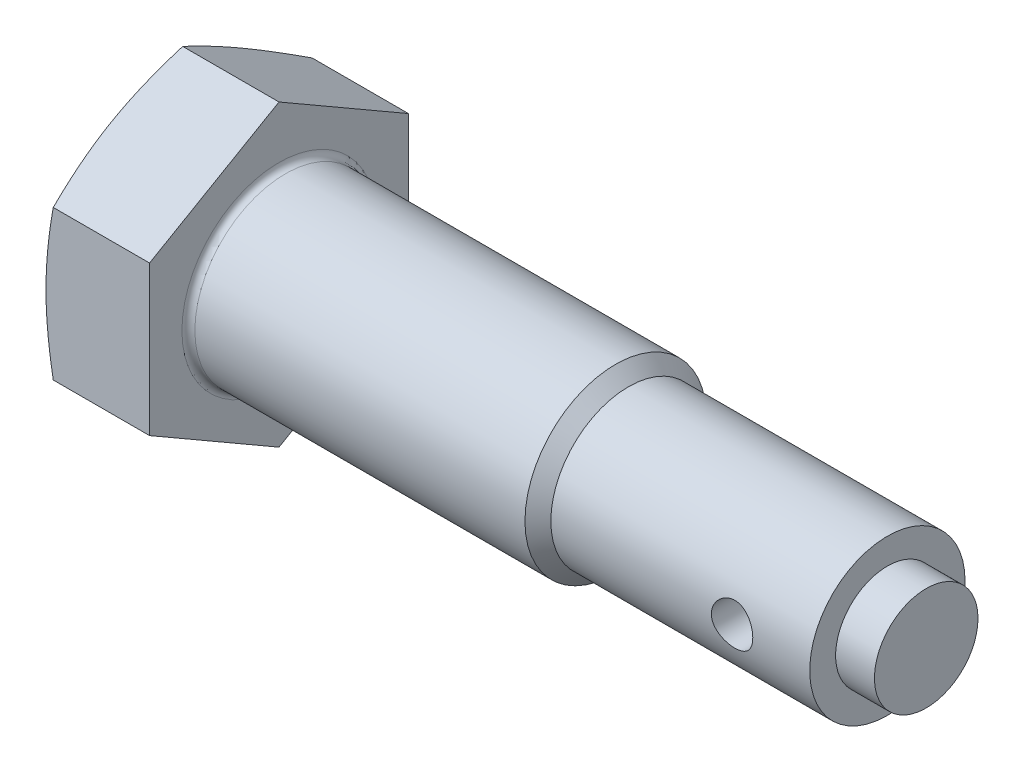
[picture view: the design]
ISO-10303-21;
HEADER;
FILE_DESCRIPTION(('STEP AP214'),'2;1');
FILE_NAME('part.step','',(''),(''),'','','');
FILE_SCHEMA(('AUTOMOTIVE_DESIGN { 1 0 10303 214 1 1 1 1 }'));
ENDSEC;
DATA;
#1=APPLICATION_CONTEXT('core data for automotive mechanical design processes');
#2=APPLICATION_PROTOCOL_DEFINITION('international standard','automotive_design',2000,#1);
#3=PRODUCT_CONTEXT('',#1,'mechanical');
#4=PRODUCT('Part','Part','',(#3));
#5=PRODUCT_RELATED_PRODUCT_CATEGORY('part','',(#4));
#6=PRODUCT_DEFINITION_FORMATION('','',#4);
#7=PRODUCT_DEFINITION_CONTEXT('part definition',#1,'design');
#8=PRODUCT_DEFINITION('design','',#6,#7);
#9=PRODUCT_DEFINITION_SHAPE('','',#8);
#10=(LENGTH_UNIT() NAMED_UNIT(*) SI_UNIT(.MILLI.,.METRE.));
#11=(NAMED_UNIT(*) PLANE_ANGLE_UNIT() SI_UNIT($,.RADIAN.));
#12=(NAMED_UNIT(*) SI_UNIT($,.STERADIAN.) SOLID_ANGLE_UNIT());
#13=UNCERTAINTY_MEASURE_WITH_UNIT(LENGTH_MEASURE(1.E-05),#10,'distance_accuracy_value','');
#14=(GEOMETRIC_REPRESENTATION_CONTEXT(3) GLOBAL_UNCERTAINTY_ASSIGNED_CONTEXT((#13)) GLOBAL_UNIT_ASSIGNED_CONTEXT((#10,
#11,#12)) REPRESENTATION_CONTEXT('',''));
#15=CARTESIAN_POINT('',(0.,0.,0.));
#16=DIRECTION('',(0.,0.,1.));
#17=DIRECTION('',(1.,0.,0.));
#18=AXIS2_PLACEMENT_3D('',#15,#16,#17);
#19=CARTESIAN_POINT('',(4.,-2.88675134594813,4.99999999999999));
#20=DIRECTION('',(0.,0.866025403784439,-0.5));
#21=DIRECTION('',(0.,0.5,0.866025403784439));
#22=AXIS2_PLACEMENT_3D('',#19,#20,#21);
#23=PLANE('',#22);
#24=CARTESIAN_POINT('',(0.281573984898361,-5.77361816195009,-0.000199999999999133));
#25=CARTESIAN_POINT('',(0.238042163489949,-5.65406193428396,0.206877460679));
#26=CARTESIAN_POINT('',(0.198442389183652,-5.53411145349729,0.414637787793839));
#27=CARTESIAN_POINT('',(0.128772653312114,-5.29343053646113,0.831509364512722));
#28=CARTESIAN_POINT('',(0.0987101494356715,-5.17269956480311,1.04062154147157));
#29=CARTESIAN_POINT('',(0.0500848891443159,-4.9317975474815,1.45787607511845));
#30=CARTESIAN_POINT('',(0.0314160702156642,-4.81163200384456,1.66600890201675));
#31=CARTESIAN_POINT('',(0.00637593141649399,-4.57101989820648,2.08276129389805));
#32=CARTESIAN_POINT('',(0.,-4.45057345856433,2.29138064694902));
#33=CARTESIAN_POINT('',(0.,-4.20968057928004,2.70861935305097));
#34=CARTESIAN_POINT('',(0.00637593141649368,-4.0892341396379,2.91723870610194));
#35=CARTESIAN_POINT('',(0.0314160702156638,-3.84862203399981,3.33399109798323));
#36=CARTESIAN_POINT('',(0.0500848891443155,-3.72845649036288,3.54212392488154));
#37=CARTESIAN_POINT('',(0.0987101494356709,-3.48755447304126,3.95937845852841));
#38=CARTESIAN_POINT('',(0.128772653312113,-3.36682350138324,4.16849063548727));
#39=CARTESIAN_POINT('',(0.198442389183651,-3.12614258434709,4.58536221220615));
#40=CARTESIAN_POINT('',(0.238042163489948,-3.00619210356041,4.79312253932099));
#41=CARTESIAN_POINT('',(0.28157398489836,-2.88663587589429,5.00019999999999));
#42=B_SPLINE_CURVE_WITH_KNOTS('',3,(#24,#25,#26,#27,#28,#29,#30,#31,#32,#33,#34,#35,#36,#37,#38,
#39,#40,#41),.UNSPECIFIED.,.F.,.F.,(4,2,2,2,2,2,2,2,4),(0.,0.729203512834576,1.45897583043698,
2.18184682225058,2.90444658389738,3.62704634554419,4.34991733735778,5.07968965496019,
5.80889316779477),.UNSPECIFIED.);
#43=CARTESIAN_POINT('',(0.28153195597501,-5.77350269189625,0.));
#44=VERTEX_POINT('',#43);
#45=CARTESIAN_POINT('',(0.,-4.33012701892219,2.5));
#46=VERTEX_POINT('',#45);
#47=EDGE_CURVE('E302',#44,#46,#42,.T.);
#48=ORIENTED_EDGE('',*,*,#47,.F.);
#49=DIRECTION('',(-1.,0.,0.));
#50=VECTOR('',#49,1.);
#51=CARTESIAN_POINT('',(4.,-5.77350269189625,0.));
#52=LINE('',#51,#50);
#53=CARTESIAN_POINT('',(4.,-5.77350269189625,0.));
#54=VERTEX_POINT('',#53);
#55=EDGE_CURVE('E166',#54,#44,#52,.T.);
#56=ORIENTED_EDGE('',*,*,#55,.F.);
#57=DIRECTION('',(0.,-0.5,-0.866025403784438));
#58=VECTOR('',#57,1.);
#59=CARTESIAN_POINT('',(4.,-2.88675134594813,4.99999999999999));
#60=LINE('',#59,#58);
#61=CARTESIAN_POINT('',(4.,-2.88675134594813,4.99999999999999));
#62=VERTEX_POINT('',#61);
#63=EDGE_CURVE('E285',#62,#54,#60,.T.);
#64=ORIENTED_EDGE('',*,*,#63,.F.);
#65=DIRECTION('',(-1.,0.,0.));
#66=VECTOR('',#65,1.);
#67=CARTESIAN_POINT('',(4.,-2.88675134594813,4.99999999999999));
#68=LINE('',#67,#66);
#69=CARTESIAN_POINT('',(0.28153195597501,-2.88675134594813,4.99999999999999));
#70=VERTEX_POINT('',#69);
#71=EDGE_CURVE('E152',#62,#70,#68,.T.);
#72=ORIENTED_EDGE('',*,*,#71,.T.);
#73=EDGE_CURVE('E150',#46,#70,#42,.T.);
#74=ORIENTED_EDGE('',*,*,#73,.F.);
#75=EDGE_LOOP('',(#48,#56,#64,#72,#74));
#76=FACE_BOUND('',#75,.T.);
#77=ADVANCED_FACE('F49',(#76),#23,.F.);
#78=CARTESIAN_POINT('',(4.,-5.77350269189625,0.));
#79=DIRECTION('',(0.,0.866025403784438,0.5));
#80=DIRECTION('',(0.,-0.5,0.866025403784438));
#81=AXIS2_PLACEMENT_3D('',#78,#79,#80);
#82=PLANE('',#81);
#83=CARTESIAN_POINT('',(0.281573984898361,-2.88663587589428,-5.00019999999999));
#84=CARTESIAN_POINT('',(0.238042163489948,-3.00619210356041,-4.79312253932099));
#85=CARTESIAN_POINT('',(0.198442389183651,-3.12614258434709,-4.58536221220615));
#86=CARTESIAN_POINT('',(0.128772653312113,-3.36682350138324,-4.16849063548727));
#87=CARTESIAN_POINT('',(0.0987101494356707,-3.48755447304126,-3.95937845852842));
#88=CARTESIAN_POINT('',(0.050084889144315,-3.72845649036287,-3.54212392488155));
#89=CARTESIAN_POINT('',(0.0314160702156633,-3.84862203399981,-3.33399109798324));
#90=CARTESIAN_POINT('',(0.00637593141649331,-4.0892341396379,-2.91723870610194));
#91=CARTESIAN_POINT('',(0.,-4.20968057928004,-2.70861935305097));
#92=CARTESIAN_POINT('',(0.,-4.45057345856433,-2.29138064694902));
#93=CARTESIAN_POINT('',(0.00637593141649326,-4.57101989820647,-2.08276129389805));
#94=CARTESIAN_POINT('',(0.0314160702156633,-4.81163200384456,-1.66600890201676));
#95=CARTESIAN_POINT('',(0.050084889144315,-4.9317975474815,-1.45787607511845));
#96=CARTESIAN_POINT('',(0.0987101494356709,-5.17269956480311,-1.04062154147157));
#97=CARTESIAN_POINT('',(0.128772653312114,-5.29343053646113,-0.831509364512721));
#98=CARTESIAN_POINT('',(0.198442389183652,-5.53411145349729,-0.414637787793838));
#99=CARTESIAN_POINT('',(0.238042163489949,-5.65406193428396,-0.206877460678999));
#100=CARTESIAN_POINT('',(0.281573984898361,-5.77361816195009,0.000199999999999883));
#101=B_SPLINE_CURVE_WITH_KNOTS('',3,(#83,#84,#85,#86,#87,#88,#89,#90,#91,#92,#93,#94,#95,#96,
#97,#98,#99,#100),.UNSPECIFIED.,.F.,.F.,(4,2,2,2,2,2,2,2,4),(0.,0.729203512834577,
1.45897583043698,2.18184682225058,2.90444658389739,3.6270463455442,4.34991733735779,
5.0796896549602,5.80889316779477),.UNSPECIFIED.);
#102=CARTESIAN_POINT('',(0.28153195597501,-2.88675134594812,-4.99999999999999));
#103=VERTEX_POINT('',#102);
#104=CARTESIAN_POINT('',(0.,-4.33012701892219,-2.5));
#105=VERTEX_POINT('',#104);
#106=EDGE_CURVE('E243',#103,#105,#101,.T.);
#107=ORIENTED_EDGE('',*,*,#106,.F.);
#108=DIRECTION('',(-1.,0.,0.));
#109=VECTOR('',#108,1.);
#110=CARTESIAN_POINT('',(4.,-2.88675134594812,-4.99999999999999));
#111=LINE('',#110,#109);
#112=CARTESIAN_POINT('',(4.,-2.88675134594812,-4.99999999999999));
#113=VERTEX_POINT('',#112);
#114=EDGE_CURVE('E161',#113,#103,#111,.T.);
#115=ORIENTED_EDGE('',*,*,#114,.F.);
#116=DIRECTION('',(0.,0.5,-0.866025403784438));
#117=VECTOR('',#116,1.);
#118=CARTESIAN_POINT('',(4.,-5.77350269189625,0.));
#119=LINE('',#118,#117);
#120=EDGE_CURVE('E281',#54,#113,#119,.T.);
#121=ORIENTED_EDGE('',*,*,#120,.F.);
#122=ORIENTED_EDGE('',*,*,#55,.T.);
#123=EDGE_CURVE('E239',#105,#44,#101,.T.);
#124=ORIENTED_EDGE('',*,*,#123,.F.);
#125=EDGE_LOOP('',(#107,#115,#121,#122,#124));
#126=FACE_BOUND('',#125,.T.);
#127=ADVANCED_FACE('F255',(#126),#82,.F.);
#128=CARTESIAN_POINT('',(4.,-2.88675134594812,-4.99999999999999));
#129=DIRECTION('',(0.,0.,1.));
#130=DIRECTION('',(1.,0.,0.));
#131=AXIS2_PLACEMENT_3D('',#128,#129,#130);
#132=PLANE('',#131);
#133=CARTESIAN_POINT('',(1.50439512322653,-7.64310251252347,-4.99999999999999));
#134=CARTESIAN_POINT('',(1.43551180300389,-7.4168844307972,-4.99999999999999));
#135=CARTESIAN_POINT('',(1.36743226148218,-7.19041704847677,-4.99999999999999));
#136=CARTESIAN_POINT('',(1.23332538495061,-6.73685676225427,-4.99999999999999));
#137=CARTESIAN_POINT('',(1.1672982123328,-6.5097638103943,-4.99999999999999));
#138=CARTESIAN_POINT('',(1.03763088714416,-6.05443677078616,-4.99999999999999));
#139=CARTESIAN_POINT('',(0.973995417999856,-5.82620134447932,-4.99999999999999));
#140=CARTESIAN_POINT('',(0.849856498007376,-5.36888148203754,-4.99999999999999));
#141=CARTESIAN_POINT('',(0.7893529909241,-5.1397970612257,-4.99999999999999));
#142=CARTESIAN_POINT('',(0.672973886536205,-4.68345086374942,-4.99999999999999));
#143=CARTESIAN_POINT('',(0.617050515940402,-4.45620133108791,-4.99999999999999));
#144=CARTESIAN_POINT('',(0.50996822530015,-4.00058448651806,-4.99999999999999));
#145=CARTESIAN_POINT('',(0.458809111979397,-3.77221722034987,-4.99999999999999));
#146=CARTESIAN_POINT('',(0.362442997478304,-3.31429429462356,-4.99999999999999));
#147=CARTESIAN_POINT('',(0.317234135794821,-3.08473902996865,-4.99999999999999));
#148=CARTESIAN_POINT('',(0.234146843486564,-2.62429577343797,-4.99999999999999));
#149=CARTESIAN_POINT('',(0.196268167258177,-2.3934078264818,-4.99999999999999));
#150=CARTESIAN_POINT('',(0.133130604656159,-1.95629809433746,-4.99999999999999));
#151=CARTESIAN_POINT('',(0.10693296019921,-1.75021318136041,-4.99999999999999));
#152=CARTESIAN_POINT('',(0.0625865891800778,-1.3371719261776,-4.99999999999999));
#153=CARTESIAN_POINT('',(0.0444376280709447,-1.13021560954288,-4.99999999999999));
#154=CARTESIAN_POINT('',(0.0170626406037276,-0.71585133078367,-4.99999999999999));
#155=CARTESIAN_POINT('',(0.00783030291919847,-0.508443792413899,-4.99999999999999));
#156=CARTESIAN_POINT('',(-0.00124400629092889,-0.0934212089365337,-4.99999999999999));
#157=CARTESIAN_POINT('',(-0.00108604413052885,0.114193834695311,-4.99999999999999));
#158=CARTESIAN_POINT('',(0.00863625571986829,0.530253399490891,-4.99999999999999));
#159=CARTESIAN_POINT('',(0.0182482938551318,0.738696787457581,-4.99999999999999));
#160=CARTESIAN_POINT('',(0.0464363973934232,1.15497131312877,-4.99999999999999));
#161=CARTESIAN_POINT('',(0.0650126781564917,1.36280243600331,-4.99999999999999));
#162=CARTESIAN_POINT('',(0.110260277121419,1.77774980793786,-4.99999999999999));
#163=CARTESIAN_POINT('',(0.136938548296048,1.98486528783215,-4.99999999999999));
#164=CARTESIAN_POINT('',(0.19730798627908,2.3980600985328,-4.99999999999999));
#165=CARTESIAN_POINT('',(0.230999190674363,2.60413942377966,-4.99999999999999));
#166=CARTESIAN_POINT('',(0.306236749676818,3.02610647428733,-4.99999999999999));
#167=CARTESIAN_POINT('',(0.348104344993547,3.24193641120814,-4.99999999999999));
#168=CARTESIAN_POINT('',(0.437228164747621,3.67248794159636,-4.99999999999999));
#169=CARTESIAN_POINT('',(0.484484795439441,3.88720945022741,-4.99999999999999));
#170=CARTESIAN_POINT('',(0.58339431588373,4.3156971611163,-4.99999999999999));
#171=CARTESIAN_POINT('',(0.635048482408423,4.52946306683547,-4.99999999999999));
#172=CARTESIAN_POINT('',(0.741913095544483,4.95609429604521,-4.99999999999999));
#173=CARTESIAN_POINT('',(0.797123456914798,5.16895964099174,-4.99999999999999));
#174=CARTESIAN_POINT('',(0.910507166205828,5.59418863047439,-4.99999999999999));
#175=CARTESIAN_POINT('',(0.96868421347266,5.80655128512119,-4.99999999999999));
#176=CARTESIAN_POINT('',(1.08740866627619,6.23061420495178,-4.99999999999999));
#177=CARTESIAN_POINT('',(1.14795610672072,6.44231446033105,-4.99999999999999));
#178=CARTESIAN_POINT('',(1.33247422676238,7.07649472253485,-4.99999999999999));
#179=CARTESIAN_POINT('',(1.45934162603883,7.49813135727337,-4.99999999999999));
#180=CARTESIAN_POINT('',(1.71694117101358,8.33511686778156,-4.99999999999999));
#181=CARTESIAN_POINT('',(1.84761520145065,8.75048377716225,-4.99999999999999));
#182=CARTESIAN_POINT('',(2.11267795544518,9.5800502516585,-4.99999999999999));
#183=CARTESIAN_POINT('',(2.24706685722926,9.99424975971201,-4.99999999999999));
#184=CARTESIAN_POINT('',(2.51803451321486,10.8201887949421,-4.99999999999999));
#185=CARTESIAN_POINT('',(2.65460302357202,11.2319316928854,-4.99999999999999));
#186=CARTESIAN_POINT('',(2.92978767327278,12.0546955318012,-4.99999999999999));
#187=CARTESIAN_POINT('',(3.06840364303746,12.4657165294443,-4.99999999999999));
#188=CARTESIAN_POINT('',(3.20773627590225,12.8764911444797,-4.99999999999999));
#189=B_SPLINE_CURVE_WITH_KNOTS('',3,(#133,#134,#135,#136,#137,#138,#139,#140,#141,#142,#143,
#144,#145,#146,#147,#148,#149,#150,#151,#152,#153,#154,#155,#156,#157,#158,#159,#160,#161,#162,
#163,#164,#165,#166,#167,#168,#169,#170,#171,#172,#173,#174,#175,#176,#177,#178,#179,#180,#181,
#182,#183,#184,#185,#186,#187,#188),.UNSPECIFIED.,.F.,.F.,(4,2,2,2,2,2,2,2,2,2,2,2,2,2,2,2,2,2,
2,2,2,2,2,2,2,2,2,4),(0.,0.709424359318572,1.41890470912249,2.12970877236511,2.84050006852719,
3.54254782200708,4.24456708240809,4.94636631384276,5.6481420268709,6.27123531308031,
6.89431044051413,7.51694422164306,8.13957360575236,8.76536065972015,9.39116274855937,
10.0175034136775,10.64384743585,11.3033228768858,11.9628480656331,12.6225653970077,
13.2822669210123,13.9428122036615,14.6033672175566,15.9242375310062,17.2305282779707,
18.5368818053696,19.8382785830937,21.139568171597),.UNSPECIFIED.);
#190=CARTESIAN_POINT('',(0.28153195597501,2.88675134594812,-4.99999999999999));
#191=VERTEX_POINT('',#190);
#192=CARTESIAN_POINT('',(0.,0.,-5.));
#193=VERTEX_POINT('',#192);
#194=EDGE_CURVE('E307',#191,#193,#189,.F.);
#195=ORIENTED_EDGE('',*,*,#194,.F.);
#196=DIRECTION('',(-1.,0.,0.));
#197=VECTOR('',#196,1.);
#198=CARTESIAN_POINT('',(4.,2.88675134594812,-4.99999999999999));
#199=LINE('',#198,#197);
#200=CARTESIAN_POINT('',(4.,2.88675134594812,-4.99999999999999));
#201=VERTEX_POINT('',#200);
#202=EDGE_CURVE('E157',#201,#191,#199,.T.);
#203=ORIENTED_EDGE('',*,*,#202,.F.);
#204=DIRECTION('',(0.,1.,0.));
#205=VECTOR('',#204,1.);
#206=CARTESIAN_POINT('',(4.,-2.88675134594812,-4.99999999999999));
#207=LINE('',#206,#205);
#208=EDGE_CURVE('E288',#113,#201,#207,.T.);
#209=ORIENTED_EDGE('',*,*,#208,.F.);
#210=ORIENTED_EDGE('',*,*,#114,.T.);
#211=EDGE_CURVE('E242',#193,#103,#189,.F.);
#212=ORIENTED_EDGE('',*,*,#211,.F.);
#213=EDGE_LOOP('',(#195,#203,#209,#210,#212));
#214=FACE_BOUND('',#213,.T.);
#215=ADVANCED_FACE('F254',(#214),#132,.F.);
#216=CARTESIAN_POINT('',(4.,2.88675134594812,-4.99999999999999));
#217=DIRECTION('',(0.,-0.866025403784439,0.5));
#218=DIRECTION('',(0.,-0.5,-0.866025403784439));
#219=AXIS2_PLACEMENT_3D('',#216,#217,#218);
#220=PLANE('',#219);
#221=CARTESIAN_POINT('',(0.281573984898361,5.77361816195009,0.000199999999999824));
#222=CARTESIAN_POINT('',(0.238042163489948,5.65406193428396,-0.206877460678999));
#223=CARTESIAN_POINT('',(0.198442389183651,5.53411145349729,-0.414637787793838));
#224=CARTESIAN_POINT('',(0.128772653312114,5.29343053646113,-0.831509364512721));
#225=CARTESIAN_POINT('',(0.0987101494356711,5.17269956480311,-1.04062154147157));
#226=CARTESIAN_POINT('',(0.0500848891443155,4.9317975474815,-1.45787607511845));
#227=CARTESIAN_POINT('',(0.0314160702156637,4.81163200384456,-1.66600890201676));
#228=CARTESIAN_POINT('',(0.00637593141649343,4.57101989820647,-2.08276129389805));
#229=CARTESIAN_POINT('',(0.,4.45057345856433,-2.29138064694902));
#230=CARTESIAN_POINT('',(0.,4.20968057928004,-2.70861935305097));
#231=CARTESIAN_POINT('',(0.00637593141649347,4.0892341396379,-2.91723870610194));
#232=CARTESIAN_POINT('',(0.0314160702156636,3.84862203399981,-3.33399109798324));
#233=CARTESIAN_POINT('',(0.0500848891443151,3.72845649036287,-3.54212392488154));
#234=CARTESIAN_POINT('',(0.0987101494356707,3.48755447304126,-3.95937845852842));
#235=CARTESIAN_POINT('',(0.128772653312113,3.36682350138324,-4.16849063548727));
#236=CARTESIAN_POINT('',(0.198442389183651,3.12614258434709,-4.58536221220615));
#237=CARTESIAN_POINT('',(0.238042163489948,3.00619210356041,-4.79312253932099));
#238=CARTESIAN_POINT('',(0.28157398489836,2.88663587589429,-5.00019999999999));
#239=B_SPLINE_CURVE_WITH_KNOTS('',3,(#221,#222,#223,#224,#225,#226,#227,#228,#229,#230,#231,
#232,#233,#234,#235,#236,#237,#238),.UNSPECIFIED.,.F.,.F.,(4,2,2,2,2,2,2,2,4),(0.,
0.729203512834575,1.45897583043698,2.18184682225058,2.90444658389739,3.62704634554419,
4.34991733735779,5.07968965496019,5.80889316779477),.UNSPECIFIED.);
#240=CARTESIAN_POINT('',(0.28153195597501,5.77350269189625,0.));
#241=VERTEX_POINT('',#240);
#242=CARTESIAN_POINT('',(0.,4.33012701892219,-2.5));
#243=VERTEX_POINT('',#242);
#244=EDGE_CURVE('E232',#241,#243,#239,.T.);
#245=ORIENTED_EDGE('',*,*,#244,.F.);
#246=DIRECTION('',(-1.,0.,0.));
#247=VECTOR('',#246,1.);
#248=CARTESIAN_POINT('',(4.,5.77350269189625,0.));
#249=LINE('',#248,#247);
#250=CARTESIAN_POINT('',(4.,5.77350269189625,0.));
#251=VERTEX_POINT('',#250);
#252=EDGE_CURVE('E153',#251,#241,#249,.T.);
#253=ORIENTED_EDGE('',*,*,#252,.F.);
#254=DIRECTION('',(0.,0.5,0.866025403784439));
#255=VECTOR('',#254,1.);
#256=CARTESIAN_POINT('',(4.,2.88675134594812,-4.99999999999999));
#257=LINE('',#256,#255);
#258=EDGE_CURVE('E291',#201,#251,#257,.T.);
#259=ORIENTED_EDGE('',*,*,#258,.F.);
#260=ORIENTED_EDGE('',*,*,#202,.T.);
#261=EDGE_CURVE('E301',#243,#191,#239,.T.);
#262=ORIENTED_EDGE('',*,*,#261,.F.);
#263=EDGE_LOOP('',(#245,#253,#259,#260,#262));
#264=FACE_BOUND('',#263,.T.);
#265=ADVANCED_FACE('F298',(#264),#220,.F.);
#266=CARTESIAN_POINT('',(4.,5.77350269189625,0.));
#267=DIRECTION('',(0.,-0.866025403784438,-0.5));
#268=DIRECTION('',(0.,0.5,-0.866025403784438));
#269=AXIS2_PLACEMENT_3D('',#266,#267,#268);
#270=PLANE('',#269);
#271=CARTESIAN_POINT('',(0.28157398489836,2.88663587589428,5.00019999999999));
#272=CARTESIAN_POINT('',(0.238042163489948,3.00619210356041,4.79312253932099));
#273=CARTESIAN_POINT('',(0.19844238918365,3.12614258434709,4.58536221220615));
#274=CARTESIAN_POINT('',(0.128772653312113,3.36682350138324,4.16849063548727));
#275=CARTESIAN_POINT('',(0.09871014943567,3.48755447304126,3.95937845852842));
#276=CARTESIAN_POINT('',(0.0500848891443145,3.72845649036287,3.54212392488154));
#277=CARTESIAN_POINT('',(0.031416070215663,3.84862203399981,3.33399109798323));
#278=CARTESIAN_POINT('',(0.00637593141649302,4.0892341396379,2.91723870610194));
#279=CARTESIAN_POINT('',(0.,4.20968057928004,2.70861935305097));
#280=CARTESIAN_POINT('',(0.,4.45057345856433,2.29138064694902));
#281=CARTESIAN_POINT('',(0.00637593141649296,4.57101989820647,2.08276129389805));
#282=CARTESIAN_POINT('',(0.0314160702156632,4.81163200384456,1.66600890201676));
#283=CARTESIAN_POINT('',(0.0500848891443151,4.9317975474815,1.45787607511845));
#284=CARTESIAN_POINT('',(0.0987101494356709,5.17269956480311,1.04062154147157));
#285=CARTESIAN_POINT('',(0.128772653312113,5.29343053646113,0.831509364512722));
#286=CARTESIAN_POINT('',(0.198442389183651,5.53411145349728,0.414637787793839));
#287=CARTESIAN_POINT('',(0.238042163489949,5.65406193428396,0.206877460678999));
#288=CARTESIAN_POINT('',(0.281573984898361,5.77361816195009,-0.000199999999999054));
#289=B_SPLINE_CURVE_WITH_KNOTS('',3,(#271,#272,#273,#274,#275,#276,#277,#278,#279,#280,#281,
#282,#283,#284,#285,#286,#287,#288),.UNSPECIFIED.,.F.,.F.,(4,2,2,2,2,2,2,2,4),(0.,
0.729203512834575,1.45897583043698,2.18184682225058,2.90444658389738,3.62704634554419,
4.34991733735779,5.07968965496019,5.80889316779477),.UNSPECIFIED.);
#290=CARTESIAN_POINT('',(0.28153195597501,2.88675134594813,4.99999999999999));
#291=VERTEX_POINT('',#290);
#292=CARTESIAN_POINT('',(0.,4.33012701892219,2.5));
#293=VERTEX_POINT('',#292);
#294=EDGE_CURVE('E131',#291,#293,#289,.T.);
#295=ORIENTED_EDGE('',*,*,#294,.F.);
#296=DIRECTION('',(-1.,0.,0.));
#297=VECTOR('',#296,1.);
#298=CARTESIAN_POINT('',(4.,2.88675134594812,4.99999999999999));
#299=LINE('',#298,#297);
#300=CARTESIAN_POINT('',(4.,2.88675134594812,4.99999999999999));
#301=VERTEX_POINT('',#300);
#302=EDGE_CURVE('E147',#301,#291,#299,.T.);
#303=ORIENTED_EDGE('',*,*,#302,.F.);
#304=DIRECTION('',(0.,-0.5,0.866025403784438));
#305=VECTOR('',#304,1.);
#306=CARTESIAN_POINT('',(4.,5.77350269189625,0.));
#307=LINE('',#306,#305);
#308=EDGE_CURVE('E293',#251,#301,#307,.T.);
#309=ORIENTED_EDGE('',*,*,#308,.F.);
#310=ORIENTED_EDGE('',*,*,#252,.T.);
#311=EDGE_CURVE('E148',#293,#241,#289,.T.);
#312=ORIENTED_EDGE('',*,*,#311,.F.);
#313=EDGE_LOOP('',(#295,#303,#309,#310,#312));
#314=FACE_BOUND('',#313,.T.);
#315=ADVANCED_FACE('F142',(#314),#270,.F.);
#316=CARTESIAN_POINT('',(4.,2.88675134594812,4.99999999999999));
#317=DIRECTION('',(0.,0.,-1.));
#318=DIRECTION('',(-1.,0.,0.));
#319=AXIS2_PLACEMENT_3D('',#316,#317,#318);
#320=PLANE('',#319);
#321=CARTESIAN_POINT('',(1.50439512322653,-7.64310251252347,4.99999999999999));
#322=CARTESIAN_POINT('',(1.43551180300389,-7.4168844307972,4.99999999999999));
#323=CARTESIAN_POINT('',(1.36743226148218,-7.19041704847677,4.99999999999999));
#324=CARTESIAN_POINT('',(1.23332538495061,-6.73685676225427,4.99999999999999));
#325=CARTESIAN_POINT('',(1.1672982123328,-6.5097638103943,4.99999999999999));
#326=CARTESIAN_POINT('',(1.03763088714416,-6.05443677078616,4.99999999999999));
#327=CARTESIAN_POINT('',(0.973995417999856,-5.82620134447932,4.99999999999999));
#328=CARTESIAN_POINT('',(0.849856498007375,-5.36888148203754,4.99999999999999));
#329=CARTESIAN_POINT('',(0.789352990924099,-5.1397970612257,4.99999999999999));
#330=CARTESIAN_POINT('',(0.672973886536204,-4.68345086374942,4.99999999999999));
#331=CARTESIAN_POINT('',(0.617050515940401,-4.45620133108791,4.99999999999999));
#332=CARTESIAN_POINT('',(0.509968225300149,-4.00058448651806,4.99999999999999));
#333=CARTESIAN_POINT('',(0.458809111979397,-3.77221722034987,4.99999999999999));
#334=CARTESIAN_POINT('',(0.362442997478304,-3.31429429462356,4.99999999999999));
#335=CARTESIAN_POINT('',(0.317234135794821,-3.08473902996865,4.99999999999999));
#336=CARTESIAN_POINT('',(0.234146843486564,-2.62429577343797,4.99999999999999));
#337=CARTESIAN_POINT('',(0.196268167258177,-2.3934078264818,4.99999999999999));
#338=CARTESIAN_POINT('',(0.133130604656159,-1.95629809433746,4.99999999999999));
#339=CARTESIAN_POINT('',(0.106932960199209,-1.75021318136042,4.99999999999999));
#340=CARTESIAN_POINT('',(0.0625865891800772,-1.3371719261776,4.99999999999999));
#341=CARTESIAN_POINT('',(0.0444376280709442,-1.13021560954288,4.99999999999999));
#342=CARTESIAN_POINT('',(0.0170626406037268,-0.715851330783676,4.99999999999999));
#343=CARTESIAN_POINT('',(0.00783030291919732,-0.508443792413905,4.99999999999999));
#344=CARTESIAN_POINT('',(-0.00124400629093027,-0.0934212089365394,4.99999999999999));
#345=CARTESIAN_POINT('',(-0.00108604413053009,0.114193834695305,4.99999999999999));
#346=CARTESIAN_POINT('',(0.008636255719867,0.530253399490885,4.99999999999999));
#347=CARTESIAN_POINT('',(0.0182482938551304,0.738696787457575,4.99999999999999));
#348=CARTESIAN_POINT('',(0.0464363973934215,1.15497131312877,4.99999999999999));
#349=CARTESIAN_POINT('',(0.0650126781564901,1.36280243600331,4.99999999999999));
#350=CARTESIAN_POINT('',(0.110260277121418,1.77774980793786,4.99999999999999));
#351=CARTESIAN_POINT('',(0.136938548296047,1.98486528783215,4.99999999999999));
#352=CARTESIAN_POINT('',(0.197307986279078,2.3980600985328,4.99999999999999));
#353=CARTESIAN_POINT('',(0.230999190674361,2.60413942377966,4.99999999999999));
#354=CARTESIAN_POINT('',(0.306236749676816,3.02610647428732,4.99999999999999));
#355=CARTESIAN_POINT('',(0.348104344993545,3.24193641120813,4.99999999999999));
#356=CARTESIAN_POINT('',(0.437228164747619,3.67248794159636,4.99999999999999));
#357=CARTESIAN_POINT('',(0.48448479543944,3.88720945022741,4.99999999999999));
#358=CARTESIAN_POINT('',(0.583394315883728,4.31569716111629,4.99999999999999));
#359=CARTESIAN_POINT('',(0.635048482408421,4.52946306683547,4.99999999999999));
#360=CARTESIAN_POINT('',(0.741913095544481,4.95609429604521,4.99999999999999));
#361=CARTESIAN_POINT('',(0.797123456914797,5.16895964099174,4.99999999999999));
#362=CARTESIAN_POINT('',(0.910507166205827,5.59418863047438,4.99999999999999));
#363=CARTESIAN_POINT('',(0.968684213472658,5.80655128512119,4.99999999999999));
#364=CARTESIAN_POINT('',(1.08740866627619,6.23061420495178,4.99999999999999));
#365=CARTESIAN_POINT('',(1.14795610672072,6.44231446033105,4.99999999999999));
#366=CARTESIAN_POINT('',(1.33247422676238,7.07649472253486,4.99999999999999));
#367=CARTESIAN_POINT('',(1.45934162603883,7.49813135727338,4.99999999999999));
#368=CARTESIAN_POINT('',(1.71694117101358,8.33511686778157,4.99999999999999));
#369=CARTESIAN_POINT('',(1.84761520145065,8.75048377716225,4.99999999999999));
#370=CARTESIAN_POINT('',(2.11267795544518,9.5800502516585,4.99999999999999));
#371=CARTESIAN_POINT('',(2.24706685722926,9.99424975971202,4.99999999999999));
#372=CARTESIAN_POINT('',(2.51803451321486,10.8201887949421,4.99999999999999));
#373=CARTESIAN_POINT('',(2.65460302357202,11.2319316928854,4.99999999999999));
#374=CARTESIAN_POINT('',(2.92978767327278,12.0546955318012,4.99999999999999));
#375=CARTESIAN_POINT('',(3.06840364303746,12.4657165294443,4.99999999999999));
#376=CARTESIAN_POINT('',(3.20773627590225,12.8764911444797,4.99999999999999));
#377=B_SPLINE_CURVE_WITH_KNOTS('',3,(#321,#322,#323,#324,#325,#326,#327,#328,#329,#330,#331,
#332,#333,#334,#335,#336,#337,#338,#339,#340,#341,#342,#343,#344,#345,#346,#347,#348,#349,#350,
#351,#352,#353,#354,#355,#356,#357,#358,#359,#360,#361,#362,#363,#364,#365,#366,#367,#368,#369,
#370,#371,#372,#373,#374,#375,#376),.UNSPECIFIED.,.F.,.F.,(4,2,2,2,2,2,2,2,2,2,2,2,2,2,2,2,2,2,
2,2,2,2,2,2,2,2,2,4),(0.,0.709424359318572,1.41890470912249,2.12970877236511,2.84050006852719,
3.54254782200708,4.24456708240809,4.94636631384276,5.6481420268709,6.27123531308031,
6.89431044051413,7.51694422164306,8.13957360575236,8.76536065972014,9.39116274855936,
10.0175034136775,10.64384743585,11.3033228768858,11.9628480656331,12.6225653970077,
13.2822669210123,13.9428122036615,14.6033672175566,15.9242375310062,17.2305282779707,
18.5368818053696,19.8382785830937,21.139568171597),.UNSPECIFIED.);
#378=CARTESIAN_POINT('',(0.,0.,4.99999999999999));
#379=VERTEX_POINT('',#378);
#380=EDGE_CURVE('E138',#70,#379,#377,.T.);
#381=ORIENTED_EDGE('',*,*,#380,.F.);
#382=ORIENTED_EDGE('',*,*,#71,.F.);
#383=DIRECTION('',(0.,-1.,0.));
#384=VECTOR('',#383,1.);
#385=CARTESIAN_POINT('',(4.,2.88675134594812,4.99999999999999));
#386=LINE('',#385,#384);
#387=EDGE_CURVE('E79',#301,#62,#386,.T.);
#388=ORIENTED_EDGE('',*,*,#387,.F.);
#389=ORIENTED_EDGE('',*,*,#302,.T.);
#390=EDGE_CURVE('E132',#379,#291,#377,.T.);
#391=ORIENTED_EDGE('',*,*,#390,.F.);
#392=EDGE_LOOP('',(#381,#382,#388,#389,#391));
#393=FACE_BOUND('',#392,.T.);
#394=ADVANCED_FACE('F155',(#393),#320,.F.);
#395=CARTESIAN_POINT('',(62.4852813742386,0.,0.));
#396=DIRECTION('',(-1.,0.,0.));
#397=DIRECTION('',(0.,0.,1.));
#398=AXIS2_PLACEMENT_3D('',#395,#396,#397);
#399=CYLINDRICAL_SURFACE('',#398,3.);
#400=CARTESIAN_POINT('',(25.3,0.,3.));
#401=CARTESIAN_POINT('',(25.2999989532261,-0.0441018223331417,2.99999933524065));
#402=CARTESIAN_POINT('',(25.2963409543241,-0.0882148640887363,2.99901794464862));
#403=CARTESIAN_POINT('',(25.2818315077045,-0.175170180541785,2.99519829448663));
#404=CARTESIAN_POINT('',(25.2709765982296,-0.218011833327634,2.9923591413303));
#405=CARTESIAN_POINT('',(25.2424513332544,-0.301156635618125,2.98513733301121));
#406=CARTESIAN_POINT('',(25.2247897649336,-0.341462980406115,2.98075666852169));
#407=CARTESIAN_POINT('',(25.1831851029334,-0.418541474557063,2.97091479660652));
#408=CARTESIAN_POINT('',(25.1592415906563,-0.455313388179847,2.96545351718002));
#409=CARTESIAN_POINT('',(25.1051665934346,-0.525131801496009,2.95389845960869));
#410=CARTESIAN_POINT('',(25.0749165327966,-0.558084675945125,2.9477938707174));
#411=CARTESIAN_POINT('',(25.0093406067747,-0.618514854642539,2.93570963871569));
#412=CARTESIAN_POINT('',(24.9740140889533,-0.645991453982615,2.92973001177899));
#413=CARTESIAN_POINT('',(24.8985407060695,-0.695145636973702,2.91846214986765));
#414=CARTESIAN_POINT('',(24.8583214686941,-0.716715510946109,2.91318755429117));
#415=CARTESIAN_POINT('',(24.7746639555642,-0.752750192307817,2.90408590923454));
#416=CARTESIAN_POINT('',(24.7312262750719,-0.76721630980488,2.9002585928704));
#417=CARTESIAN_POINT('',(24.6434017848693,-0.7883076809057,2.89459646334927));
#418=CARTESIAN_POINT('',(24.5990585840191,-0.795102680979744,2.89271859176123));
#419=CARTESIAN_POINT('',(24.5098249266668,-0.801188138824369,2.89103932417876));
#420=CARTESIAN_POINT('',(24.4649345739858,-0.800479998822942,2.89123754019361));
#421=CARTESIAN_POINT('',(24.3772058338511,-0.791714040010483,2.89364951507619));
#422=CARTESIAN_POINT('',(24.3343451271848,-0.783861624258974,2.89580694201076));
#423=CARTESIAN_POINT('',(24.2505726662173,-0.761358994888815,2.90180405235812));
#424=CARTESIAN_POINT('',(24.2096610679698,-0.746708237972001,2.90564387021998));
#425=CARTESIAN_POINT('',(24.1304127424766,-0.710857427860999,2.91462264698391));
#426=CARTESIAN_POINT('',(24.0921102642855,-0.68958536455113,2.91977577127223));
#427=CARTESIAN_POINT('',(24.0195463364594,-0.641146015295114,2.93079291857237));
#428=CARTESIAN_POINT('',(23.9852856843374,-0.613977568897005,2.93665708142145));
#429=CARTESIAN_POINT('',(23.9206044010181,-0.553466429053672,2.94867004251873));
#430=CARTESIAN_POINT('',(23.890345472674,-0.519951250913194,2.95482188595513));
#431=CARTESIAN_POINT('',(23.8358444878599,-0.448247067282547,2.96654552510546));
#432=CARTESIAN_POINT('',(23.811602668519,-0.410057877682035,2.97211729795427));
#433=CARTESIAN_POINT('',(23.7697528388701,-0.32983930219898,2.98208728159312));
#434=CARTESIAN_POINT('',(23.7521740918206,-0.287793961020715,2.98648029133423));
#435=CARTESIAN_POINT('',(23.7243811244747,-0.201200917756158,2.99356017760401));
#436=CARTESIAN_POINT('',(23.7141652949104,-0.15665376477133,2.996247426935));
#437=CARTESIAN_POINT('',(23.7016420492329,-0.0677016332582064,2.99955663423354));
#438=CARTESIAN_POINT('',(23.6991147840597,-0.0233296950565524,3.00023598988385));
#439=CARTESIAN_POINT('',(23.7014332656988,0.0652040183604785,2.99961788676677));
#440=CARTESIAN_POINT('',(23.7062782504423,0.109365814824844,2.99832063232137));
#441=CARTESIAN_POINT('',(23.723023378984,0.195440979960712,2.99393214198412));
#442=CARTESIAN_POINT('',(23.7348008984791,0.237379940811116,2.99087210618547));
#443=CARTESIAN_POINT('',(23.7649343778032,0.318682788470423,2.98330517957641));
#444=CARTESIAN_POINT('',(23.7832910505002,0.358046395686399,2.9787981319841));
#445=CARTESIAN_POINT('',(23.8264695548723,0.433935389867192,2.96870264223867));
#446=CARTESIAN_POINT('',(23.8514109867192,0.470390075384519,2.96309474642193));
#447=CARTESIAN_POINT('',(23.9069006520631,0.538673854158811,2.95144580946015));
#448=CARTESIAN_POINT('',(23.9374499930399,0.570502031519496,2.94540468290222));
#449=CARTESIAN_POINT('',(24.0043142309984,0.629555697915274,2.9333589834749));
#450=CARTESIAN_POINT('',(24.0407674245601,0.656626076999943,2.92736024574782));
#451=CARTESIAN_POINT('',(24.1178258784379,0.704268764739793,2.91626578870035));
#452=CARTESIAN_POINT('',(24.1584309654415,0.724841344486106,2.91117003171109));
#453=CARTESIAN_POINT('',(24.2424381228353,0.758749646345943,2.9025170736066));
#454=CARTESIAN_POINT('',(24.2858223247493,0.772127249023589,2.89895099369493));
#455=CARTESIAN_POINT('',(24.3743357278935,0.791364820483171,2.89375930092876));
#456=CARTESIAN_POINT('',(24.4194644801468,0.797226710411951,2.89213319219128));
#457=CARTESIAN_POINT('',(24.508597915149,0.801155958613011,2.89104697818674));
#458=CARTESIAN_POINT('',(24.5525909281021,0.799472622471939,2.89151759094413));
#459=CARTESIAN_POINT('',(24.6396414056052,0.788937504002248,2.89440958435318));
#460=CARTESIAN_POINT('',(24.6826988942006,0.780085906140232,2.89683091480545));
#461=CARTESIAN_POINT('',(24.7663423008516,0.755610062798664,2.903310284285));
#462=CARTESIAN_POINT('',(24.8069447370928,0.740038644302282,2.90735554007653));
#463=CARTESIAN_POINT('',(24.8849915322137,0.702606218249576,2.91662727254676));
#464=CARTESIAN_POINT('',(24.9224353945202,0.680744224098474,2.92185393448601));
#465=CARTESIAN_POINT('',(24.9942921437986,0.630595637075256,2.93309168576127));
#466=CARTESIAN_POINT('',(25.0285834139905,0.602138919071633,2.93912133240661));
#467=CARTESIAN_POINT('',(25.0919849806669,0.5399322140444,2.95118201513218));
#468=CARTESIAN_POINT('',(25.1210940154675,0.506180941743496,2.95721305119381));
#469=CARTESIAN_POINT('',(25.1739168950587,0.43347199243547,2.96875124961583));
#470=CARTESIAN_POINT('',(25.1975020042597,0.39441838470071,2.97424444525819));
#471=CARTESIAN_POINT('',(25.2377349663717,0.312755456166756,2.9839352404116));
#472=CARTESIAN_POINT('',(25.2543872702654,0.270148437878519,2.98813367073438));
#473=CARTESIAN_POINT('',(25.2781101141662,0.189749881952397,2.99421901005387));
#474=CARTESIAN_POINT('',(25.286299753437,0.152304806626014,2.99637108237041));
#475=CARTESIAN_POINT('',(25.2972448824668,0.0765759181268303,2.99926179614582));
#476=CARTESIAN_POINT('',(25.30000090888,0.0382921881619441,3.00000057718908));
#477=CARTESIAN_POINT('',(25.3,0.,3.));
#478=B_SPLINE_CURVE_WITH_KNOTS('',3,(#400,#401,#402,#403,#404,#405,#406,#407,#408,#409,#410,
#411,#412,#413,#414,#415,#416,#417,#418,#419,#420,#421,#422,#423,#424,#425,#426,#427,#428,#429,
#430,#431,#432,#433,#434,#435,#436,#437,#438,#439,#440,#441,#442,#443,#444,#445,#446,#447,#448,
#449,#450,#451,#452,#453,#454,#455,#456,#457,#458,#459,#460,#461,#462,#463,#464,#465,#466,#467,
#468,#469,#470,#471,#472,#473,#474,#475,#476,#477),.UNSPECIFIED.,.T.,.F.,(4,2,2,2,2,2,2,2,2,2,2,
2,2,2,2,2,2,2,2,2,2,2,2,2,2,2,2,2,2,2,2,2,2,2,2,2,2,2,4),(0.,0.132165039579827,0.26439369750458,
0.396452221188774,0.5285195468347,0.663339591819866,0.798176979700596,0.935330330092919,
1.0724583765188,1.20648863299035,1.34049384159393,1.47076400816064,1.60104458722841,
1.73279469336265,1.86457075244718,2.00064503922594,2.13672468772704,2.27339523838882,
2.41003590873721,2.54273087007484,2.67541211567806,2.80581414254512,2.93623030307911,
3.06920114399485,3.2021982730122,3.33894598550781,3.47568799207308,3.61162519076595,
3.7475276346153,3.87897336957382,4.01041572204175,4.14084306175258,4.27129086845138,
4.40557735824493,4.53989649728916,4.67708900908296,4.81419330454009,4.92895927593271,
5.0437139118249),.UNSPECIFIED.);
#479=CARTESIAN_POINT('',(25.3,0.,3.));
#480=VERTEX_POINT('',#479);
#481=EDGE_CURVE('E53',#480,#480,#478,.T.);
#482=ORIENTED_EDGE('',*,*,#481,.T.);
#483=EDGE_LOOP('',(#482));
#484=FACE_BOUND('',#483,.T.);
#485=CARTESIAN_POINT('',(25.3,0.,-3.));
#486=CARTESIAN_POINT('',(25.2999989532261,0.0441018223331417,-2.99999933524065));
#487=CARTESIAN_POINT('',(25.2963409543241,0.0882148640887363,-2.99901794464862));
#488=CARTESIAN_POINT('',(25.2818315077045,0.175170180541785,-2.99519829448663));
#489=CARTESIAN_POINT('',(25.2709765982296,0.218011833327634,-2.9923591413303));
#490=CARTESIAN_POINT('',(25.2424513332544,0.301156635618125,-2.98513733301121));
#491=CARTESIAN_POINT('',(25.2247897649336,0.341462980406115,-2.98075666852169));
#492=CARTESIAN_POINT('',(25.1831851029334,0.418541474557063,-2.97091479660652));
#493=CARTESIAN_POINT('',(25.1592415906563,0.455313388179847,-2.96545351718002));
#494=CARTESIAN_POINT('',(25.1051665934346,0.525131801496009,-2.95389845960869));
#495=CARTESIAN_POINT('',(25.0749165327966,0.558084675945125,-2.9477938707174));
#496=CARTESIAN_POINT('',(25.0093406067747,0.618514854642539,-2.93570963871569));
#497=CARTESIAN_POINT('',(24.9740140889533,0.645991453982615,-2.92973001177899));
#498=CARTESIAN_POINT('',(24.8985407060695,0.695145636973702,-2.91846214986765));
#499=CARTESIAN_POINT('',(24.8583214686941,0.716715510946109,-2.91318755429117));
#500=CARTESIAN_POINT('',(24.7746639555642,0.752750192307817,-2.90408590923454));
#501=CARTESIAN_POINT('',(24.7312262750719,0.76721630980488,-2.9002585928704));
#502=CARTESIAN_POINT('',(24.6434017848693,0.7883076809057,-2.89459646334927));
#503=CARTESIAN_POINT('',(24.5990585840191,0.795102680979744,-2.89271859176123));
#504=CARTESIAN_POINT('',(24.5098249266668,0.801188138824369,-2.89103932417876));
#505=CARTESIAN_POINT('',(24.4649345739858,0.800479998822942,-2.89123754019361));
#506=CARTESIAN_POINT('',(24.3772058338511,0.791714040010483,-2.89364951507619));
#507=CARTESIAN_POINT('',(24.3343451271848,0.783861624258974,-2.89580694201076));
#508=CARTESIAN_POINT('',(24.2505726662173,0.761358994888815,-2.90180405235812));
#509=CARTESIAN_POINT('',(24.2096610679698,0.746708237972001,-2.90564387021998));
#510=CARTESIAN_POINT('',(24.1304127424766,0.710857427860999,-2.91462264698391));
#511=CARTESIAN_POINT('',(24.0921102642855,0.68958536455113,-2.91977577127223));
#512=CARTESIAN_POINT('',(24.0195463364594,0.641146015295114,-2.93079291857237));
#513=CARTESIAN_POINT('',(23.9852856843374,0.613977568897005,-2.93665708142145));
#514=CARTESIAN_POINT('',(23.9206044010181,0.553466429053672,-2.94867004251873));
#515=CARTESIAN_POINT('',(23.890345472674,0.519951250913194,-2.95482188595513));
#516=CARTESIAN_POINT('',(23.8358444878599,0.448247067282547,-2.96654552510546));
#517=CARTESIAN_POINT('',(23.811602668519,0.410057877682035,-2.97211729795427));
#518=CARTESIAN_POINT('',(23.7697528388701,0.32983930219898,-2.98208728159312));
#519=CARTESIAN_POINT('',(23.7521740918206,0.287793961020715,-2.98648029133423));
#520=CARTESIAN_POINT('',(23.7243811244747,0.201200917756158,-2.99356017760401));
#521=CARTESIAN_POINT('',(23.7141652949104,0.15665376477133,-2.996247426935));
#522=CARTESIAN_POINT('',(23.7016420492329,0.0677016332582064,-2.99955663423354));
#523=CARTESIAN_POINT('',(23.6991147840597,0.0233296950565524,-3.00023598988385));
#524=CARTESIAN_POINT('',(23.7014332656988,-0.0652040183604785,-2.99961788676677));
#525=CARTESIAN_POINT('',(23.7062782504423,-0.109365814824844,-2.99832063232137));
#526=CARTESIAN_POINT('',(23.723023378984,-0.195440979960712,-2.99393214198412));
#527=CARTESIAN_POINT('',(23.7348008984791,-0.237379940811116,-2.99087210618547));
#528=CARTESIAN_POINT('',(23.7649343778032,-0.318682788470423,-2.98330517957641));
#529=CARTESIAN_POINT('',(23.7832910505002,-0.358046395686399,-2.9787981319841));
#530=CARTESIAN_POINT('',(23.8264695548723,-0.433935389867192,-2.96870264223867));
#531=CARTESIAN_POINT('',(23.8514109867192,-0.470390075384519,-2.96309474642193));
#532=CARTESIAN_POINT('',(23.9069006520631,-0.538673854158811,-2.95144580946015));
#533=CARTESIAN_POINT('',(23.9374499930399,-0.570502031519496,-2.94540468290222));
#534=CARTESIAN_POINT('',(24.0043142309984,-0.629555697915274,-2.9333589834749));
#535=CARTESIAN_POINT('',(24.0407674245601,-0.656626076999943,-2.92736024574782));
#536=CARTESIAN_POINT('',(24.1178258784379,-0.704268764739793,-2.91626578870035));
#537=CARTESIAN_POINT('',(24.1584309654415,-0.724841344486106,-2.91117003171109));
#538=CARTESIAN_POINT('',(24.2424381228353,-0.758749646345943,-2.9025170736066));
#539=CARTESIAN_POINT('',(24.2858223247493,-0.772127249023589,-2.89895099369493));
#540=CARTESIAN_POINT('',(24.3743357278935,-0.791364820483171,-2.89375930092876));
#541=CARTESIAN_POINT('',(24.4194644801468,-0.797226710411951,-2.89213319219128));
#542=CARTESIAN_POINT('',(24.508597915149,-0.801155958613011,-2.89104697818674));
#543=CARTESIAN_POINT('',(24.5525909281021,-0.799472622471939,-2.89151759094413));
#544=CARTESIAN_POINT('',(24.6396414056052,-0.788937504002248,-2.89440958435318));
#545=CARTESIAN_POINT('',(24.6826988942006,-0.780085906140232,-2.89683091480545));
#546=CARTESIAN_POINT('',(24.7663423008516,-0.755610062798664,-2.903310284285));
#547=CARTESIAN_POINT('',(24.8069447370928,-0.740038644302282,-2.90735554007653));
#548=CARTESIAN_POINT('',(24.8849915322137,-0.702606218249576,-2.91662727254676));
#549=CARTESIAN_POINT('',(24.9224353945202,-0.680744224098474,-2.92185393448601));
#550=CARTESIAN_POINT('',(24.9942921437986,-0.630595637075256,-2.93309168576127));
#551=CARTESIAN_POINT('',(25.0285834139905,-0.602138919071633,-2.93912133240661));
#552=CARTESIAN_POINT('',(25.0919849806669,-0.5399322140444,-2.95118201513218));
#553=CARTESIAN_POINT('',(25.1210940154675,-0.506180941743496,-2.95721305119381));
#554=CARTESIAN_POINT('',(25.1739168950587,-0.43347199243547,-2.96875124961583));
#555=CARTESIAN_POINT('',(25.1975020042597,-0.39441838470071,-2.97424444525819));
#556=CARTESIAN_POINT('',(25.2377349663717,-0.312755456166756,-2.9839352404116));
#557=CARTESIAN_POINT('',(25.2543872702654,-0.270148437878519,-2.98813367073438));
#558=CARTESIAN_POINT('',(25.2781101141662,-0.189749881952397,-2.99421901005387));
#559=CARTESIAN_POINT('',(25.286299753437,-0.152304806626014,-2.99637108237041));
#560=CARTESIAN_POINT('',(25.2972448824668,-0.0765759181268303,-2.99926179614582));
#561=CARTESIAN_POINT('',(25.30000090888,-0.0382921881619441,-3.00000057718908));
#562=CARTESIAN_POINT('',(25.3,0.,-3.));
#563=B_SPLINE_CURVE_WITH_KNOTS('',3,(#485,#486,#487,#488,#489,#490,#491,#492,#493,#494,#495,
#496,#497,#498,#499,#500,#501,#502,#503,#504,#505,#506,#507,#508,#509,#510,#511,#512,#513,#514,
#515,#516,#517,#518,#519,#520,#521,#522,#523,#524,#525,#526,#527,#528,#529,#530,#531,#532,#533,
#534,#535,#536,#537,#538,#539,#540,#541,#542,#543,#544,#545,#546,#547,#548,#549,#550,#551,#552,
#553,#554,#555,#556,#557,#558,#559,#560,#561,#562),.UNSPECIFIED.,.T.,.F.,(4,2,2,2,2,2,2,2,2,2,2,
2,2,2,2,2,2,2,2,2,2,2,2,2,2,2,2,2,2,2,2,2,2,2,2,2,2,2,4),(0.,0.132165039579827,0.26439369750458,
0.396452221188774,0.5285195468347,0.663339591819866,0.798176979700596,0.935330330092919,
1.0724583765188,1.20648863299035,1.34049384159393,1.47076400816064,1.60104458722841,
1.73279469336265,1.86457075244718,2.00064503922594,2.13672468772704,2.27339523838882,
2.41003590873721,2.54273087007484,2.67541211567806,2.80581414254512,2.93623030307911,
3.06920114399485,3.2021982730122,3.33894598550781,3.47568799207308,3.61162519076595,
3.7475276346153,3.87897336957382,4.01041572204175,4.14084306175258,4.27129086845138,
4.40557735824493,4.53989649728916,4.67708900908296,4.81419330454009,4.92895927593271,
5.0437139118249),.UNSPECIFIED.);
#564=CARTESIAN_POINT('',(25.3,0.,-3.));
#565=VERTEX_POINT('',#564);
#566=EDGE_CURVE('E181',#565,#565,#563,.T.);
#567=ORIENTED_EDGE('',*,*,#566,.T.);
#568=EDGE_LOOP('',(#567));
#569=FACE_BOUND('',#568,.T.);
#570=CARTESIAN_POINT('',(17.5,0.,0.));
#571=DIRECTION('',(1.,0.,0.));
#572=DIRECTION('',(0.,0.,-1.));
#573=AXIS2_PLACEMENT_3D('',#570,#571,#572);
#574=CIRCLE('',#573,3.);
#575=CARTESIAN_POINT('',(17.5,0.,-3.));
#576=VERTEX_POINT('',#575);
#577=EDGE_CURVE('E13',#576,#576,#574,.T.);
#578=ORIENTED_EDGE('',*,*,#577,.T.);
#579=EDGE_LOOP('',(#578));
#580=FACE_BOUND('',#579,.T.);
#581=CARTESIAN_POINT('',(27.5,0.,0.));
#582=DIRECTION('',(1.,0.,0.));
#583=DIRECTION('',(0.,0.,-1.));
#584=AXIS2_PLACEMENT_3D('',#581,#582,#583);
#585=CIRCLE('',#584,3.);
#586=CARTESIAN_POINT('',(27.5,0.,-3.));
#587=VERTEX_POINT('',#586);
#588=EDGE_CURVE('E167',#587,#587,#585,.T.);
#589=ORIENTED_EDGE('',*,*,#588,.F.);
#590=EDGE_LOOP('',(#589));
#591=FACE_BOUND('',#590,.T.);
#592=ADVANCED_FACE('F186',(#484,#569,#580,#591),#399,.T.);
#593=CARTESIAN_POINT('',(4.,0.,9.99999999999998));
#594=DIRECTION('',(-1.,0.,0.));
#595=DIRECTION('',(0.,0.,1.));
#596=AXIS2_PLACEMENT_3D('',#593,#594,#595);
#597=PLANE('',#596);
#598=CARTESIAN_POINT('',(4.,0.,0.));
#599=DIRECTION('',(-1.,0.,0.));
#600=DIRECTION('',(0.,0.,1.));
#601=AXIS2_PLACEMENT_3D('',#598,#599,#600);
#602=CIRCLE('',#601,3.75);
#603=CARTESIAN_POINT('',(4.,0.,3.75));
#604=VERTEX_POINT('',#603);
#605=EDGE_CURVE('E61',#604,#604,#602,.T.);
#606=ORIENTED_EDGE('',*,*,#605,.T.);
#607=EDGE_LOOP('',(#606));
#608=FACE_BOUND('',#607,.T.);
#609=ORIENTED_EDGE('',*,*,#63,.T.);
#610=ORIENTED_EDGE('',*,*,#120,.T.);
#611=ORIENTED_EDGE('',*,*,#208,.T.);
#612=ORIENTED_EDGE('',*,*,#258,.T.);
#613=ORIENTED_EDGE('',*,*,#308,.T.);
#614=ORIENTED_EDGE('',*,*,#387,.T.);
#615=EDGE_LOOP('',(#609,#610,#611,#612,#613,#614));
#616=FACE_BOUND('',#615,.T.);
#617=ADVANCED_FACE('F278',(#608,#616),#597,.F.);
#618=CARTESIAN_POINT('',(17.,0.,0.));
#619=DIRECTION('',(-1.,0.,0.));
#620=DIRECTION('',(0.,0.,1.));
#621=AXIS2_PLACEMENT_3D('',#618,#619,#620);
#622=CYLINDRICAL_SURFACE('',#621,3.5);
#623=CARTESIAN_POINT('',(4.25,0.,0.));
#624=DIRECTION('',(-1.,0.,0.));
#625=DIRECTION('',(0.,0.,1.));
#626=AXIS2_PLACEMENT_3D('',#623,#624,#625);
#627=CIRCLE('',#626,3.5);
#628=CARTESIAN_POINT('',(4.25,0.,3.5));
#629=VERTEX_POINT('',#628);
#630=EDGE_CURVE('E178',#629,#629,#627,.F.);
#631=CARTESIAN_POINT('',(17.,0.,0.));
#632=DIRECTION('',(1.,0.,0.));
#633=DIRECTION('',(0.,0.,-1.));
#634=AXIS2_PLACEMENT_3D('',#631,#632,#633);
#635=CIRCLE('',#634,3.5);
#636=CARTESIAN_POINT('',(17.,0.,3.5));
#637=VERTEX_POINT('',#636);
#638=EDGE_CURVE('E174',#637,#637,#635,.T.);
#639=CARTESIAN_POINT('',(4.25,0.,3.5));
#640=CARTESIAN_POINT('',(4.3828125,0.,3.5));
#641=CARTESIAN_POINT('',(4.515625,0.,3.5));
#642=CARTESIAN_POINT('',(4.78125,0.,3.5));
#643=CARTESIAN_POINT('',(4.9140625,0.,3.5));
#644=CARTESIAN_POINT('',(5.1796875,0.,3.5));
#645=CARTESIAN_POINT('',(5.3125,0.,3.5));
#646=CARTESIAN_POINT('',(5.578125,0.,3.5));
#647=CARTESIAN_POINT('',(5.7109375,0.,3.5));
#648=CARTESIAN_POINT('',(5.9765625,0.,3.5));
#649=CARTESIAN_POINT('',(6.109375,0.,3.5));
#650=CARTESIAN_POINT('',(6.375,0.,3.5));
#651=CARTESIAN_POINT('',(6.5078125,0.,3.5));
#652=CARTESIAN_POINT('',(6.7734375,0.,3.5));
#653=CARTESIAN_POINT('',(6.90625,0.,3.5));
#654=CARTESIAN_POINT('',(7.171875,0.,3.5));
#655=CARTESIAN_POINT('',(7.3046875,0.,3.5));
#656=CARTESIAN_POINT('',(7.5703125,0.,3.5));
#657=CARTESIAN_POINT('',(7.703125,0.,3.5));
#658=CARTESIAN_POINT('',(7.96875,0.,3.5));
#659=CARTESIAN_POINT('',(8.1015625,0.,3.5));
#660=CARTESIAN_POINT('',(8.3671875,0.,3.5));
#661=CARTESIAN_POINT('',(8.5,0.,3.5));
#662=CARTESIAN_POINT('',(8.765625,0.,3.5));
#663=CARTESIAN_POINT('',(8.8984375,0.,3.5));
#664=CARTESIAN_POINT('',(9.1640625,0.,3.5));
#665=CARTESIAN_POINT('',(9.296875,0.,3.5));
#666=CARTESIAN_POINT('',(9.5625,0.,3.5));
#667=CARTESIAN_POINT('',(9.6953125,0.,3.5));
#668=CARTESIAN_POINT('',(9.9609375,0.,3.5));
#669=CARTESIAN_POINT('',(10.09375,0.,3.5));
#670=CARTESIAN_POINT('',(10.359375,0.,3.5));
#671=CARTESIAN_POINT('',(10.4921875,0.,3.5));
#672=CARTESIAN_POINT('',(10.7578125,0.,3.5));
#673=CARTESIAN_POINT('',(10.890625,0.,3.5));
#674=CARTESIAN_POINT('',(11.15625,0.,3.5));
#675=CARTESIAN_POINT('',(11.2890625,0.,3.5));
#676=CARTESIAN_POINT('',(11.5546875,0.,3.5));
#677=CARTESIAN_POINT('',(11.6875,0.,3.5));
#678=CARTESIAN_POINT('',(11.953125,0.,3.5));
#679=CARTESIAN_POINT('',(12.0859375,0.,3.5));
#680=CARTESIAN_POINT('',(12.3515625,0.,3.5));
#681=CARTESIAN_POINT('',(12.484375,0.,3.5));
#682=CARTESIAN_POINT('',(12.75,0.,3.5));
#683=CARTESIAN_POINT('',(12.8828125,0.,3.5));
#684=CARTESIAN_POINT('',(13.1484375,0.,3.5));
#685=CARTESIAN_POINT('',(13.28125,0.,3.5));
#686=CARTESIAN_POINT('',(13.546875,0.,3.5));
#687=CARTESIAN_POINT('',(13.6796875,0.,3.5));
#688=CARTESIAN_POINT('',(13.9453125,0.,3.5));
#689=CARTESIAN_POINT('',(14.078125,0.,3.5));
#690=CARTESIAN_POINT('',(14.34375,0.,3.5));
#691=CARTESIAN_POINT('',(14.4765625,0.,3.5));
#692=CARTESIAN_POINT('',(14.7421875,0.,3.5));
#693=CARTESIAN_POINT('',(14.875,0.,3.5));
#694=CARTESIAN_POINT('',(15.140625,0.,3.5));
#695=CARTESIAN_POINT('',(15.2734375,0.,3.5));
#696=CARTESIAN_POINT('',(15.5390625,0.,3.5));
#697=CARTESIAN_POINT('',(15.671875,0.,3.5));
#698=CARTESIAN_POINT('',(15.9375,0.,3.5));
#699=CARTESIAN_POINT('',(16.0703125,0.,3.5));
#700=CARTESIAN_POINT('',(16.3359375,0.,3.5));
#701=CARTESIAN_POINT('',(16.46875,0.,3.5));
#702=CARTESIAN_POINT('',(16.734375,0.,3.5));
#703=CARTESIAN_POINT('',(16.8671875,0.,3.5));
#704=CARTESIAN_POINT('',(17.,0.,3.5));
#705=B_SPLINE_CURVE_WITH_KNOTS('',3,(#639,#640,#641,#642,#643,#644,#645,#646,#647,#648,#649,
#650,#651,#652,#653,#654,#655,#656,#657,#658,#659,#660,#661,#662,#663,#664,#665,#666,#667,#668,
#669,#670,#671,#672,#673,#674,#675,#676,#677,#678,#679,#680,#681,#682,#683,#684,#685,#686,#687,
#688,#689,#690,#691,#692,#693,#694,#695,#696,#697,#698,#699,#700,#701,#702,#703,#704),
.UNSPECIFIED.,.F.,.F.,(4,2,2,2,2,2,2,2,2,2,2,2,2,2,2,2,2,2,2,2,2,2,2,2,2,2,2,2,2,2,2,2,4),(0.,
0.3984375,0.796875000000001,1.1953125,1.59375,1.9921875,2.390625,2.7890625,3.1875,3.5859375,
3.984375,4.3828125,4.78125,5.1796875,5.578125,5.9765625,6.375,6.7734375,7.171875,7.5703125,
7.96875,8.3671875,8.765625,9.1640625,9.5625,9.9609375,10.359375,10.7578125,11.15625,11.5546875,
11.953125,12.3515625,12.75),.UNSPECIFIED.);
#706=EDGE_CURVE('BSEAM276',#629,#637,#705,.T.);
#707=ORIENTED_EDGE('',*,*,#630,.T.);
#708=ORIENTED_EDGE('',*,*,#638,.F.);
#709=ORIENTED_EDGE('',*,*,#706,.T.);
#710=ORIENTED_EDGE('',*,*,#706,.F.);
#711=EDGE_LOOP('',(#707,#709,#708,#710));
#712=FACE_BOUND('',#711,.T.);
#713=ADVANCED_FACE('F276',(#712),#622,.T.);
#714=CARTESIAN_POINT('',(27.5,0.,0.));
#715=DIRECTION('',(1.,0.,0.));
#716=DIRECTION('',(0.,0.,-1.));
#717=AXIS2_PLACEMENT_3D('',#714,#715,#716);
#718=PLANE('',#717);
#719=CARTESIAN_POINT('',(27.5,0.,0.));
#720=DIRECTION('',(1.,0.,0.));
#721=DIRECTION('',(0.,0.,-1.));
#722=AXIS2_PLACEMENT_3D('',#719,#720,#721);
#723=CIRCLE('',#722,2.);
#724=CARTESIAN_POINT('',(27.5,0.,-2.));
#725=VERTEX_POINT('',#724);
#726=EDGE_CURVE('E173',#725,#725,#723,.T.);
#727=ORIENTED_EDGE('',*,*,#726,.F.);
#728=EDGE_LOOP('',(#727));
#729=FACE_BOUND('',#728,.T.);
#730=ORIENTED_EDGE('',*,*,#588,.T.);
#731=EDGE_LOOP('',(#730));
#732=FACE_BOUND('',#731,.T.);
#733=ADVANCED_FACE('F277',(#729,#732),#718,.T.);
#734=CARTESIAN_POINT('',(27.5,0.,0.));
#735=DIRECTION('',(1.,0.,0.));
#736=DIRECTION('',(0.,0.,-1.));
#737=AXIS2_PLACEMENT_3D('',#734,#735,#736);
#738=CYLINDRICAL_SURFACE('',#737,2.);
#739=ORIENTED_EDGE('',*,*,#726,.T.);
#740=EDGE_LOOP('',(#739));
#741=FACE_BOUND('',#740,.T.);
#742=CARTESIAN_POINT('',(29.,0.,0.));
#743=DIRECTION('',(1.,0.,0.));
#744=DIRECTION('',(0.,0.,-1.));
#745=AXIS2_PLACEMENT_3D('',#742,#743,#744);
#746=CIRCLE('',#745,2.);
#747=CARTESIAN_POINT('',(29.,0.,-2.));
#748=VERTEX_POINT('',#747);
#749=EDGE_CURVE('E290',#748,#748,#746,.T.);
#750=ORIENTED_EDGE('',*,*,#749,.F.);
#751=EDGE_LOOP('',(#750));
#752=FACE_BOUND('',#751,.T.);
#753=ADVANCED_FACE('F204',(#741,#752),#738,.T.);
#754=CARTESIAN_POINT('',(29.,0.,9.99999999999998));
#755=DIRECTION('',(-1.,0.,0.));
#756=DIRECTION('',(0.,0.,1.));
#757=AXIS2_PLACEMENT_3D('',#754,#755,#756);
#758=PLANE('',#757);
#759=ORIENTED_EDGE('',*,*,#749,.T.);
#760=EDGE_LOOP('',(#759));
#761=FACE_BOUND('',#760,.T.);
#762=ADVANCED_FACE('F328',(#761),#758,.F.);
#763=CARTESIAN_POINT('',(0.,0.,0.));
#764=DIRECTION('',(1.,0.,0.));
#765=DIRECTION('',(0.,0.,-1.));
#766=AXIS2_PLACEMENT_3D('',#763,#764,#765);
#767=CONICAL_SURFACE('',#766,5.,1.22173047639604);
#768=ORIENTED_EDGE('',*,*,#73,.T.);
#769=ORIENTED_EDGE('',*,*,#380,.T.);
#770=CARTESIAN_POINT('',(0.,0.,0.));
#771=DIRECTION('',(-1.,0.,0.));
#772=DIRECTION('',(0.,0.,1.));
#773=AXIS2_PLACEMENT_3D('',#770,#771,#772);
#774=CIRCLE('',#773,5.);
#775=EDGE_CURVE('E72',#46,#379,#774,.T.);
#776=ORIENTED_EDGE('',*,*,#775,.F.);
#777=EDGE_LOOP('',(#768,#769,#776));
#778=FACE_BOUND('',#777,.T.);
#779=ADVANCED_FACE('F326',(#778),#767,.T.);
#780=ORIENTED_EDGE('',*,*,#123,.T.);
#781=ORIENTED_EDGE('',*,*,#47,.T.);
#782=EDGE_CURVE('E176',#105,#46,#774,.T.);
#783=ORIENTED_EDGE('',*,*,#782,.F.);
#784=EDGE_LOOP('',(#780,#781,#783));
#785=FACE_BOUND('',#784,.T.);
#786=ADVANCED_FACE('F320',(#785),#767,.T.);
#787=ORIENTED_EDGE('',*,*,#211,.T.);
#788=ORIENTED_EDGE('',*,*,#106,.T.);
#789=EDGE_CURVE('E315',#193,#105,#774,.T.);
#790=ORIENTED_EDGE('',*,*,#789,.F.);
#791=EDGE_LOOP('',(#787,#788,#790));
#792=FACE_BOUND('',#791,.T.);
#793=ADVANCED_FACE('F202',(#792),#767,.T.);
#794=ORIENTED_EDGE('',*,*,#194,.T.);
#795=EDGE_CURVE('E322',#243,#193,#774,.T.);
#796=ORIENTED_EDGE('',*,*,#795,.F.);
#797=ORIENTED_EDGE('',*,*,#261,.T.);
#798=EDGE_LOOP('',(#794,#796,#797));
#799=FACE_BOUND('',#798,.T.);
#800=ADVANCED_FACE('F200',(#799),#767,.T.);
#801=ORIENTED_EDGE('',*,*,#244,.T.);
#802=EDGE_CURVE('E180',#293,#243,#774,.T.);
#803=ORIENTED_EDGE('',*,*,#802,.F.);
#804=ORIENTED_EDGE('',*,*,#311,.T.);
#805=EDGE_LOOP('',(#801,#803,#804));
#806=FACE_BOUND('',#805,.T.);
#807=ADVANCED_FACE('F205',(#806),#767,.T.);
#808=ORIENTED_EDGE('',*,*,#294,.T.);
#809=CARTESIAN_POINT('',(0.,0.,0.));
#810=DIRECTION('',(-1.,0.,0.));
#811=DIRECTION('',(0.,0.,1.));
#812=AXIS2_PLACEMENT_3D('',#809,#810,#811);
#813=CIRCLE('',#812,5.);
#814=EDGE_CURVE('E137',#379,#293,#813,.T.);
#815=ORIENTED_EDGE('',*,*,#814,.F.);
#816=ORIENTED_EDGE('',*,*,#390,.T.);
#817=EDGE_LOOP('',(#808,#815,#816));
#818=FACE_BOUND('',#817,.T.);
#819=ADVANCED_FACE('F134',(#818),#767,.T.);
#820=CARTESIAN_POINT('',(0.,0.,9.99999999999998));
#821=DIRECTION('',(-1.,0.,0.));
#822=DIRECTION('',(0.,0.,1.));
#823=AXIS2_PLACEMENT_3D('',#820,#821,#822);
#824=PLANE('',#823);
#825=ORIENTED_EDGE('',*,*,#775,.T.);
#826=ORIENTED_EDGE('',*,*,#814,.T.);
#827=ORIENTED_EDGE('',*,*,#802,.T.);
#828=ORIENTED_EDGE('',*,*,#795,.T.);
#829=ORIENTED_EDGE('',*,*,#789,.T.);
#830=ORIENTED_EDGE('',*,*,#782,.T.);
#831=EDGE_LOOP('',(#825,#826,#827,#828,#829,#830));
#832=FACE_BOUND('',#831,.T.);
#833=ADVANCED_FACE('F261',(#832),#824,.T.);
#834=CARTESIAN_POINT('',(4.25,0.,0.));
#835=DIRECTION('',(-1.,0.,0.));
#836=DIRECTION('',(0.,0.,1.));
#837=AXIS2_PLACEMENT_3D('',#834,#835,#836);
#838=TOROIDAL_SURFACE('',#837,3.75,0.25);
#839=ORIENTED_EDGE('',*,*,#605,.F.);
#840=EDGE_LOOP('',(#839));
#841=FACE_BOUND('',#840,.T.);
#842=ORIENTED_EDGE('',*,*,#630,.F.);
#843=EDGE_LOOP('',(#842));
#844=FACE_BOUND('',#843,.T.);
#845=ADVANCED_FACE('F263',(#841,#844),#838,.F.);
#846=CARTESIAN_POINT('',(17.5,0.,0.));
#847=DIRECTION('',(-1.,0.,0.));
#848=DIRECTION('',(0.,0.,1.));
#849=AXIS2_PLACEMENT_3D('',#846,#847,#848);
#850=CONICAL_SURFACE('',#849,3.,0.78539816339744);
#851=ORIENTED_EDGE('',*,*,#638,.T.);
#852=EDGE_LOOP('',(#851));
#853=FACE_BOUND('',#852,.T.);
#854=ORIENTED_EDGE('',*,*,#577,.F.);
#855=EDGE_LOOP('',(#854));
#856=FACE_BOUND('',#855,.T.);
#857=ADVANCED_FACE('F55',(#853,#856),#850,.T.);
#858=CARTESIAN_POINT('',(24.5,0.,-5.));
#859=DIRECTION('',(0.,0.,1.));
#860=DIRECTION('',(1.,0.,0.));
#861=AXIS2_PLACEMENT_3D('',#858,#859,#860);
#862=CYLINDRICAL_SURFACE('',#861,0.799999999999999);
#863=ORIENTED_EDGE('',*,*,#566,.F.);
#864=EDGE_LOOP('',(#863));
#865=FACE_BOUND('',#864,.T.);
#866=ORIENTED_EDGE('',*,*,#481,.F.);
#867=EDGE_LOOP('',(#866));
#868=FACE_BOUND('',#867,.T.);
#869=ADVANCED_FACE('F195',(#865,#868),#862,.F.);
#870=CLOSED_SHELL('',(#77,#127,#215,#265,#315,#394,#592,#617,#713,#733,#753,#762,#779,#786,#793,
#800,#807,#819,#833,#845,#857,#869));
#871=MANIFOLD_SOLID_BREP('B2',#870);
#872=ADVANCED_BREP_SHAPE_REPRESENTATION('',(#18,#871),#14);
#873=SHAPE_DEFINITION_REPRESENTATION(#9,#872);
ENDSEC;
END-ISO-10303-21;
